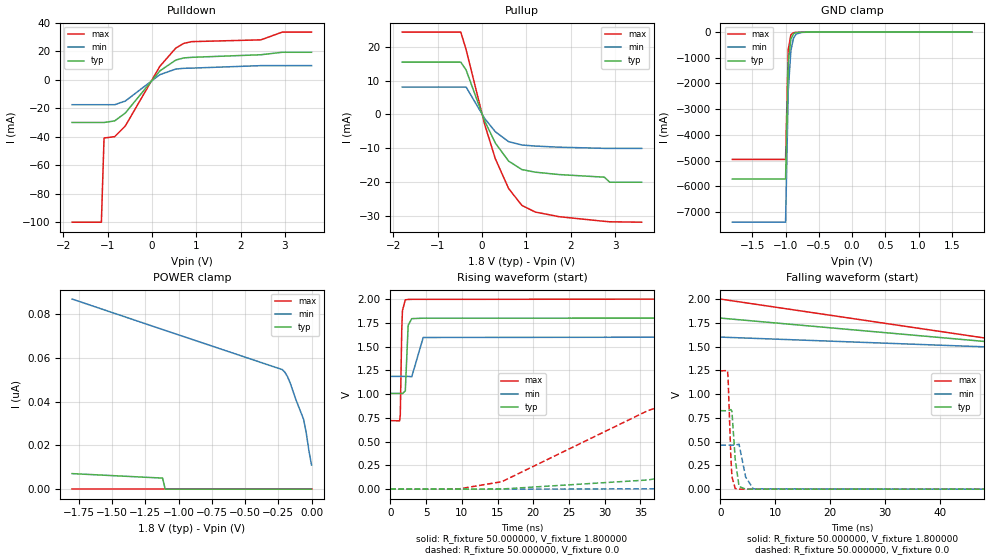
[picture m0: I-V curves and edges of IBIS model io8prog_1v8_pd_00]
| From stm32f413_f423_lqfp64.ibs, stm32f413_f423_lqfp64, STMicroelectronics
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[Model]  io8prog_1v8_pd_00
Model_type I/O
Polarity   Non-Inverting
Enable   Active-Low
Vinl =   0.540000V
Vinh =   1.260000V
Vmeas =  0.900000V
Cref =   100.000000pF
Rref =   1.000000k
Vref =   1.800000V
C_comp   2.595400pF   2.437600pF   2.808600pF
[Temperature Range]   25.000000   0.125000k   -40.000000
[Pullup Reference]   1.800000V   1.600000V   2.000000V
[Pulldown Reference]   0.0V   0.0V   0.0V
[POWER Clamp Reference]   1.800000V   1.600000V   2.000000V
[GND Clamp Reference]   0.0V   0.0V   0.0V
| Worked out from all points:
|   slope of the pulldown table from 0 to 0.27 V, typ, clamps not added: 31 ohm
|   slope of the pullup table from 0 to 0.27 V, typ, clamps not added: 34.9 ohm
|   GND clamp passes 1 mA (typ) near -0.57 V on its own axis
|   rising waveform, R_fixture 50.000000, V_fixture 1.800000: 20-80 % time 213ps typ, 327ps min, 178ps max; typ from 1.01 V to 1.8 V
|   rising waveform, R_fixture 50.000000, V_fixture 0.0: 20-80 % time 42.7ns typ, 83.8ns min, 21ns max; typ from 0 V to 0.825 V
|   falling waveform, R_fixture 50.000000, V_fixture 1.800000: 20-80 % time 93.2ns typ, 131ns min, 90.3ns max; typ from 1.8 V to 1.01 V
|   falling waveform, R_fixture 50.000000, V_fixture 0.0: 20-80 % time 640ps typ, 954ps min, 471ps max; typ from 0.825 V to 0 V
[Pulldown]
|Voltage   I(typ)   I(min)   I(max)
-1.8V     -30mA      -17.52mA   -100mA
-1.14V    -30mA      -17.52mA   -100mA
-1.08V    -30mA      -17.52mA   -40.9mA
-840mV    -28.88mA   -17.52mA   -39.94mA
-600mV    -23.35mA   -14.94mA   -32.45mA
180mV     6.236mA    3.598mA    9.492mA
540mV     13.85mA    7.499mA    22.29mA
720mV     15.32mA    8.029mA    25.55mA
900mV     15.74mA    8.167mA    26.76mA
2.46V     17.56mA    9.911mA    28.01mA
2.94V     19.29mA    9.911mA    33.46mA
3.6V      19.29mA    9.911mA    33.46mA
[Pullup]
|Voltage   I(typ)   I(min)   I(max)
-1.8V     15.46mA    8.103mA    24.33mA
-480mV    15.46mA    8.103mA    24.33mA
-360mV    13.15mA    8.103mA    19.18mA
60mV      -1.95mA    -1.198mA   -2.977mA
300mV     -8.441mA   -5.092mA   -13.07mA
600mV     -13.77mA   -8.025mA   -21.88mA
900mV     -16.27mA   -9.02mA    -26.86mA
1.2V      -17.03mA   -9.318mA   -28.8mA
1.74V     -17.74mA   -9.658mA   -30.18mA
2.76V     -18.51mA   -10mA      -31.55mA
2.88V     -20mA      -10mA      -31.68mA
3.6V      -20mA      -10mA      -31.8mA
[GND_clamp]
|Voltage   I(typ)   I(min)   I(max)
-1.8V     -5.722A    -7.401A    -4.956A
-1V       -5.722A    -7.401A    -4.956A
-960mV    -1.203A    -2.294A    -680.3mA
-920mV    -260.8mA   -717.4mA   -103.7mA
-880mV    -62.28mA   -228.9mA   -23.86mA
-840mV    -19.06mA   -76.33mA   -11.32mA
-760mV    -5.585mA   -11.67mA   -6.214mA
-640mV    -2.06mA    -2.422mA   -2.211mA
1.8V      44.31uA    33.68uA    51.4uA
[POWER_clamp]
|Voltage   I(typ)   I(min)   I(max)
-1.8V     7.116nA    87.04nA    0A
-1.12V    5.066nA    73.1nA     0A
-1.1V     0A         72.68nA    0A
-220mV    0A         54.75nA    0A
-200mV    0A         53.5nA     0A
-180mV    0A         51.44nA    0A
-160mV    0A         48.56nA    0A
-120mV    0A         41.39nA    0A
-60mV     0A         32.03nA    0A
-40mV     0A         25.87nA    0A
-20mV     0A         17.74nA    0A
0V        0A         11.07nA    0A
[Ramp]
| variable   typ   min   max
dV/dt_r  0.49513/42.67574n   0.27767/83.67942n   0.74652/20.98980n
dV/dt_f  0.47544/41.75477n   0.24804/72.86106n   0.76697/23.31042n
R_load = 50.000000
[Rising Waveform]
R_fixture= 50.000000
V_fixture= 1.800000
V_fixture_min= 1.600000
V_fixture_max= 2.000000
|time   V(typ)   V(min)   V(max)
0s        1.007V     1.186V     720.9mV
1.301ns   1.007V     1.186V     718.5mV
1.401ns   1.007V     1.186V     779mV
1.602ns   1.006V     1.186V     1.663V
1.702ns   1.005V     1.186V     1.878V
2.102ns   1.033V     1.186V     1.991V
2.503ns   1.723V     1.186V     1.995V
3.003ns   1.793V     1.182V     1.996V
4.605ns   1.798V     1.595V     1.996V
49.85ns   1.799V     1.599V     1.999V
[Rising Waveform]
R_fixture= 50.000000
V_fixture= 0.0
V_fixture_min= 0.0
V_fixture_max= 0.0
|time   V(typ)   V(min)   V(max)
0s        3.439nV    233.3nV    1.357nV
9.61ns    -102.3uV   -44.98uV   2.773mV
15.62ns   1.701mV    -33.48uV   78.86mV
36.04ns   96.65mV    3.517mV    826.2mV
45.65ns   217.3mV    9.684mV    1.063V
70.87ns   546.2mV    53.19mV    1.222V
94.89ns   718mV      140.1mV    1.241V
115.3ns   781.3mV    221.2mV    1.243V
193.4ns   822.9mV    410.8mV    1.244V
598.2ns   825.2mV    462.8mV    1.244V
[Falling Waveform]
R_fixture= 50.000000
V_fixture= 1.800000
V_fixture_min= 1.600000
V_fixture_max= 2.000000
|time   V(typ)   V(min)   V(max)
0s        1.799V     1.599V     1.999V
150.2ns   1.033V     1.28V      723.5mV
300.3ns   1.007V     1.192V     720.9mV
450.5ns   1.007V     1.187V     720.9mV
14.86us   1.007V     1.186V     720.9mV
[Falling Waveform]
R_fixture= 50.000000
V_fixture= 0.0
V_fixture_min= 0.0
V_fixture_max= 0.0
|time   V(typ)   V(min)   V(max)
0s        825.2mV    462.8mV    1.244V
1.301ns   824.6mV    462.8mV    1.247V
1.401ns   824.3mV    462.8mV    1.168V
1.902ns   836.8mV    462.8mV    346.3mV
2.102ns   819.4mV    462.5mV    132.1mV
2.703ns   314.8mV    462.4mV    6.363mV
3.403ns   27.9mV     473.1mV    489.6uV
4.605ns   460.7uV    127.5mV    139.8uV
6.006ns   40.71uV    3.393mV    126.6uV
49.85ns   3.439nV    233.3nV    1.357nV
